VERSION 5.8 ;
BUSBITCHARS "[]" ;
DIVIDERCHAR "/" ;
UNITS
    DATABASE MICRONS 1000 ;
END UNITS

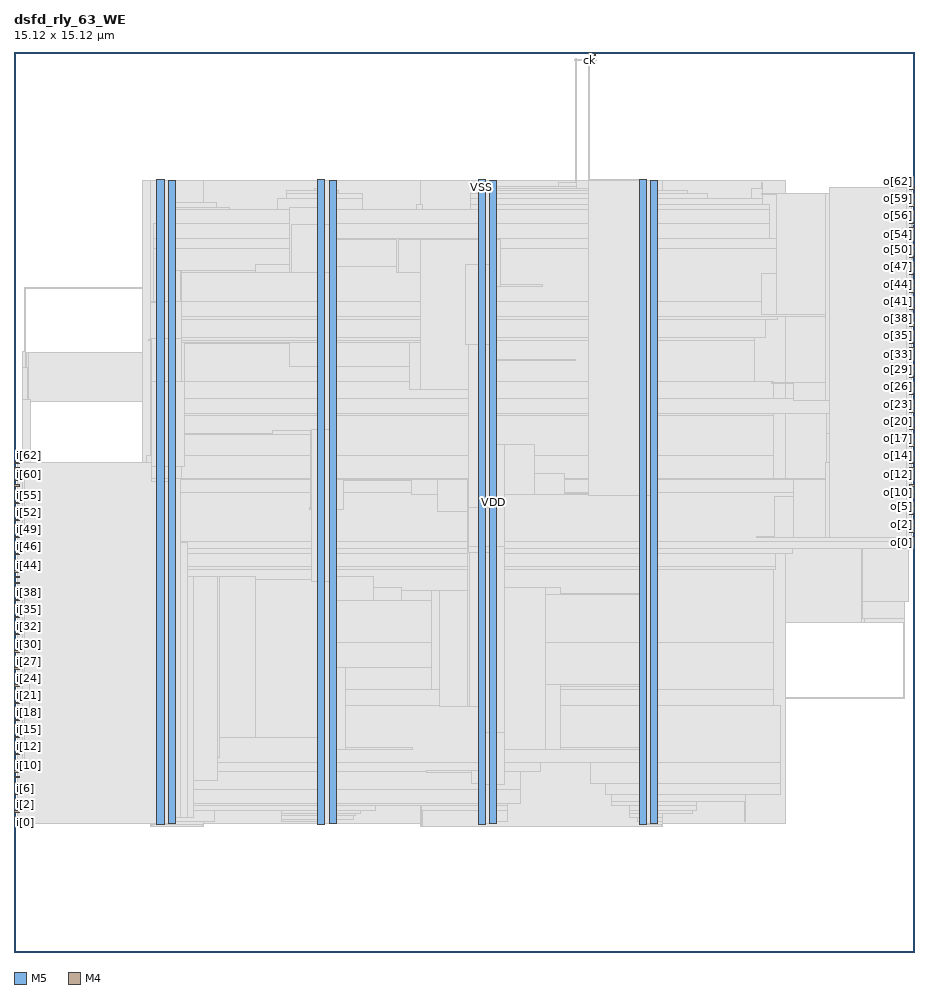
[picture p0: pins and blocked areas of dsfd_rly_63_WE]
MACRO dsfd_rly_63_WE
  FOREIGN dsfd_rly_63_WE 0 0 ;
  CLASS BLOCK ;
  SIZE 15.12 BY 15.12 ;
  PIN ck
    DIRECTION INPUT ;
    USE SIGNAL ;
    PORT
      LAYER M5 ;
        RECT  9.648 15.036 9.672 15.12 ;
    END
  END ck
  PIN i[0]
    DIRECTION INPUT ;
    USE SIGNAL ;
    PORT
      LAYER M4 ;
        RECT  0 2.16 0.084 2.184 ;
    END
  END i[0]
  PIN i[10]
    DIRECTION INPUT ;
    USE SIGNAL ;
    PORT
      LAYER M4 ;
        RECT  0 3.12 0.084 3.144 ;
    END
  END i[10]
  PIN i[11]
    DIRECTION INPUT ;
    USE SIGNAL ;
    PORT
      LAYER M4 ;
        RECT  0 3.216 0.084 3.24 ;
    END
  END i[11]
  PIN i[12]
    DIRECTION INPUT ;
    USE SIGNAL ;
    PORT
      LAYER M4 ;
        RECT  0 3.312 0.084 3.336 ;
    END
  END i[12]
  PIN i[13]
    DIRECTION INPUT ;
    USE SIGNAL ;
    PORT
      LAYER M4 ;
        RECT  0 3.408 0.084 3.432 ;
    END
  END i[13]
  PIN i[14]
    DIRECTION INPUT ;
    USE SIGNAL ;
    PORT
      LAYER M4 ;
        RECT  0 3.504 0.084 3.528 ;
    END
  END i[14]
  PIN i[15]
    DIRECTION INPUT ;
    USE SIGNAL ;
    PORT
      LAYER M4 ;
        RECT  0 3.6 0.084 3.624 ;
    END
  END i[15]
  PIN i[16]
    DIRECTION INPUT ;
    USE SIGNAL ;
    PORT
      LAYER M4 ;
        RECT  0 3.696 0.084 3.72 ;
    END
  END i[16]
  PIN i[17]
    DIRECTION INPUT ;
    USE SIGNAL ;
    PORT
      LAYER M4 ;
        RECT  0 3.792 0.084 3.816 ;
    END
  END i[17]
  PIN i[18]
    DIRECTION INPUT ;
    USE SIGNAL ;
    PORT
      LAYER M4 ;
        RECT  0 3.888 0.084 3.912 ;
    END
  END i[18]
  PIN i[19]
    DIRECTION INPUT ;
    USE SIGNAL ;
    PORT
      LAYER M4 ;
        RECT  0 3.984 0.084 4.008 ;
    END
  END i[19]
  PIN i[1]
    DIRECTION INPUT ;
    USE SIGNAL ;
    PORT
      LAYER M4 ;
        RECT  0 2.256 0.084 2.28 ;
    END
  END i[1]
  PIN i[20]
    DIRECTION INPUT ;
    USE SIGNAL ;
    PORT
      LAYER M4 ;
        RECT  0 4.08 0.084 4.104 ;
    END
  END i[20]
  PIN i[21]
    DIRECTION INPUT ;
    USE SIGNAL ;
    PORT
      LAYER M4 ;
        RECT  0 4.176 0.084 4.2 ;
    END
  END i[21]
  PIN i[22]
    DIRECTION INPUT ;
    USE SIGNAL ;
    PORT
      LAYER M4 ;
        RECT  0 4.272 0.084 4.296 ;
    END
  END i[22]
  PIN i[23]
    DIRECTION INPUT ;
    USE SIGNAL ;
    PORT
      LAYER M4 ;
        RECT  0 4.368 0.084 4.392 ;
    END
  END i[23]
  PIN i[24]
    DIRECTION INPUT ;
    USE SIGNAL ;
    PORT
      LAYER M4 ;
        RECT  0 4.464 0.084 4.488 ;
    END
  END i[24]
  PIN i[25]
    DIRECTION INPUT ;
    USE SIGNAL ;
    PORT
      LAYER M4 ;
        RECT  0 4.56 0.084 4.584 ;
    END
  END i[25]
  PIN i[26]
    DIRECTION INPUT ;
    USE SIGNAL ;
    PORT
      LAYER M4 ;
        RECT  0 4.656 0.084 4.68 ;
    END
  END i[26]
  PIN i[27]
    DIRECTION INPUT ;
    USE SIGNAL ;
    PORT
      LAYER M4 ;
        RECT  0 4.752 0.084 4.776 ;
    END
  END i[27]
  PIN i[28]
    DIRECTION INPUT ;
    USE SIGNAL ;
    PORT
      LAYER M4 ;
        RECT  0 4.848 0.084 4.872 ;
    END
  END i[28]
  PIN i[29]
    DIRECTION INPUT ;
    USE SIGNAL ;
    PORT
      LAYER M4 ;
        RECT  0 4.944 0.084 4.968 ;
    END
  END i[29]
  PIN i[2]
    DIRECTION INPUT ;
    USE SIGNAL ;
    PORT
      LAYER M4 ;
        RECT  0 2.352 0.084 2.376 ;
    END
  END i[2]
  PIN i[30]
    DIRECTION INPUT ;
    USE SIGNAL ;
    PORT
      LAYER M4 ;
        RECT  0 5.04 0.084 5.064 ;
    END
  END i[30]
  PIN i[31]
    DIRECTION INPUT ;
    USE SIGNAL ;
    PORT
      LAYER M4 ;
        RECT  0 5.136 0.084 5.16 ;
    END
  END i[31]
  PIN i[32]
    DIRECTION INPUT ;
    USE SIGNAL ;
    PORT
      LAYER M4 ;
        RECT  0 5.328 0.084 5.352 ;
    END
  END i[32]
  PIN i[33]
    DIRECTION INPUT ;
    USE SIGNAL ;
    PORT
      LAYER M4 ;
        RECT  0 5.424 0.084 5.448 ;
    END
  END i[33]
  PIN i[34]
    DIRECTION INPUT ;
    USE SIGNAL ;
    PORT
      LAYER M4 ;
        RECT  0 5.52 0.084 5.544 ;
    END
  END i[34]
  PIN i[35]
    DIRECTION INPUT ;
    USE SIGNAL ;
    PORT
      LAYER M4 ;
        RECT  0 5.616 0.084 5.64 ;
    END
  END i[35]
  PIN i[36]
    DIRECTION INPUT ;
    USE SIGNAL ;
    PORT
      LAYER M4 ;
        RECT  0 5.712 0.084 5.736 ;
    END
  END i[36]
  PIN i[37]
    DIRECTION INPUT ;
    USE SIGNAL ;
    PORT
      LAYER M4 ;
        RECT  0 5.808 0.084 5.832 ;
    END
  END i[37]
  PIN i[38]
    DIRECTION INPUT ;
    USE SIGNAL ;
    PORT
      LAYER M4 ;
        RECT  0 5.904 0.084 5.928 ;
    END
  END i[38]
  PIN i[39]
    DIRECTION INPUT ;
    USE SIGNAL ;
    PORT
      LAYER M4 ;
        RECT  0 6 0.084 6.024 ;
    END
  END i[39]
  PIN i[3]
    DIRECTION INPUT ;
    USE SIGNAL ;
    PORT
      LAYER M4 ;
        RECT  0 2.448 0.084 2.472 ;
    END
  END i[3]
  PIN i[40]
    DIRECTION INPUT ;
    USE SIGNAL ;
    PORT
      LAYER M4 ;
        RECT  0 6.096 0.084 6.12 ;
    END
  END i[40]
  PIN i[41]
    DIRECTION INPUT ;
    USE SIGNAL ;
    PORT
      LAYER M4 ;
        RECT  0 6.192 0.084 6.216 ;
    END
  END i[41]
  PIN i[42]
    DIRECTION INPUT ;
    USE SIGNAL ;
    PORT
      LAYER M4 ;
        RECT  0 6.288 0.084 6.312 ;
    END
  END i[42]
  PIN i[43]
    DIRECTION INPUT ;
    USE SIGNAL ;
    PORT
      LAYER M4 ;
        RECT  0 6.384 0.084 6.408 ;
    END
  END i[43]
  PIN i[44]
    DIRECTION INPUT ;
    USE SIGNAL ;
    PORT
      LAYER M4 ;
        RECT  0 6.48 0.084 6.504 ;
    END
  END i[44]
  PIN i[45]
    DIRECTION INPUT ;
    USE SIGNAL ;
    PORT
      LAYER M4 ;
        RECT  0 6.576 0.084 6.6 ;
    END
  END i[45]
  PIN i[46]
    DIRECTION INPUT ;
    USE SIGNAL ;
    PORT
      LAYER M4 ;
        RECT  0 6.672 0.084 6.696 ;
    END
  END i[46]
  PIN i[47]
    DIRECTION INPUT ;
    USE SIGNAL ;
    PORT
      LAYER M4 ;
        RECT  0 6.768 0.084 6.792 ;
    END
  END i[47]
  PIN i[48]
    DIRECTION INPUT ;
    USE SIGNAL ;
    PORT
      LAYER M4 ;
        RECT  0 6.864 0.084 6.888 ;
    END
  END i[48]
  PIN i[49]
    DIRECTION INPUT ;
    USE SIGNAL ;
    PORT
      LAYER M4 ;
        RECT  0 6.96 0.084 6.984 ;
    END
  END i[49]
  PIN i[4]
    DIRECTION INPUT ;
    USE SIGNAL ;
    PORT
      LAYER M4 ;
        RECT  0 2.544 0.084 2.568 ;
    END
  END i[4]
  PIN i[50]
    DIRECTION INPUT ;
    USE SIGNAL ;
    PORT
      LAYER M4 ;
        RECT  0 7.056 0.084 7.08 ;
    END
  END i[50]
  PIN i[51]
    DIRECTION INPUT ;
    USE SIGNAL ;
    PORT
      LAYER M4 ;
        RECT  0 7.152 0.084 7.176 ;
    END
  END i[51]
  PIN i[52]
    DIRECTION INPUT ;
    USE SIGNAL ;
    PORT
      LAYER M4 ;
        RECT  0 7.248 0.084 7.272 ;
    END
  END i[52]
  PIN i[53]
    DIRECTION INPUT ;
    USE SIGNAL ;
    PORT
      LAYER M4 ;
        RECT  0 7.344 0.084 7.368 ;
    END
  END i[53]
  PIN i[54]
    DIRECTION INPUT ;
    USE SIGNAL ;
    PORT
      LAYER M4 ;
        RECT  0 7.44 0.084 7.464 ;
    END
  END i[54]
  PIN i[55]
    DIRECTION INPUT ;
    USE SIGNAL ;
    PORT
      LAYER M4 ;
        RECT  0 7.536 0.084 7.56 ;
    END
  END i[55]
  PIN i[56]
    DIRECTION INPUT ;
    USE SIGNAL ;
    PORT
      LAYER M4 ;
        RECT  0 7.632 0.084 7.656 ;
    END
  END i[56]
  PIN i[57]
    DIRECTION INPUT ;
    USE SIGNAL ;
    PORT
      LAYER M4 ;
        RECT  0 7.728 0.084 7.752 ;
    END
  END i[57]
  PIN i[58]
    DIRECTION INPUT ;
    USE SIGNAL ;
    PORT
      LAYER M4 ;
        RECT  0 7.824 0.084 7.848 ;
    END
  END i[58]
  PIN i[59]
    DIRECTION INPUT ;
    USE SIGNAL ;
    PORT
      LAYER M4 ;
        RECT  0 7.92 0.084 7.944 ;
    END
  END i[59]
  PIN i[5]
    DIRECTION INPUT ;
    USE SIGNAL ;
    PORT
      LAYER M4 ;
        RECT  0 2.64 0.084 2.664 ;
    END
  END i[5]
  PIN i[60]
    DIRECTION INPUT ;
    USE SIGNAL ;
    PORT
      LAYER M4 ;
        RECT  0 8.016 0.084 8.04 ;
    END
  END i[60]
  PIN i[61]
    DIRECTION INPUT ;
    USE SIGNAL ;
    PORT
      LAYER M4 ;
        RECT  0 8.112 0.084 8.136 ;
    END
  END i[61]
  PIN i[62]
    DIRECTION INPUT ;
    USE SIGNAL ;
    PORT
      LAYER M4 ;
        RECT  0 8.208 0.084 8.232 ;
    END
  END i[62]
  PIN i[6]
    DIRECTION INPUT ;
    USE SIGNAL ;
    PORT
      LAYER M4 ;
        RECT  0 2.736 0.084 2.76 ;
    END
  END i[6]
  PIN i[7]
    DIRECTION INPUT ;
    USE SIGNAL ;
    PORT
      LAYER M4 ;
        RECT  0 2.832 0.084 2.856 ;
    END
  END i[7]
  PIN i[8]
    DIRECTION INPUT ;
    USE SIGNAL ;
    PORT
      LAYER M4 ;
        RECT  0 2.928 0.084 2.952 ;
    END
  END i[8]
  PIN i[9]
    DIRECTION INPUT ;
    USE SIGNAL ;
    PORT
      LAYER M4 ;
        RECT  0 3.024 0.084 3.048 ;
    END
  END i[9]
  PIN o[0]
    DIRECTION OUTPUT ;
    USE SIGNAL ;
    PORT
      LAYER M4 ;
        RECT  15.036 6.864 15.12 6.888 ;
    END
  END o[0]
  PIN o[10]
    DIRECTION OUTPUT ;
    USE SIGNAL ;
    PORT
      LAYER M4 ;
        RECT  15.036 7.824 15.12 7.848 ;
    END
  END o[10]
  PIN o[11]
    DIRECTION OUTPUT ;
    USE SIGNAL ;
    PORT
      LAYER M4 ;
        RECT  15.036 7.92 15.12 7.944 ;
    END
  END o[11]
  PIN o[12]
    DIRECTION OUTPUT ;
    USE SIGNAL ;
    PORT
      LAYER M4 ;
        RECT  15.036 8.016 15.12 8.04 ;
    END
  END o[12]
  PIN o[13]
    DIRECTION OUTPUT ;
    USE SIGNAL ;
    PORT
      LAYER M4 ;
        RECT  15.036 8.112 15.12 8.136 ;
    END
  END o[13]
  PIN o[14]
    DIRECTION OUTPUT ;
    USE SIGNAL ;
    PORT
      LAYER M4 ;
        RECT  15.036 8.208 15.12 8.232 ;
    END
  END o[14]
  PIN o[15]
    DIRECTION OUTPUT ;
    USE SIGNAL ;
    PORT
      LAYER M4 ;
        RECT  15.036 8.304 15.12 8.328 ;
    END
  END o[15]
  PIN o[16]
    DIRECTION OUTPUT ;
    USE SIGNAL ;
    PORT
      LAYER M4 ;
        RECT  15.036 8.4 15.12 8.424 ;
    END
  END o[16]
  PIN o[17]
    DIRECTION OUTPUT ;
    USE SIGNAL ;
    PORT
      LAYER M4 ;
        RECT  15.036 8.496 15.12 8.52 ;
    END
  END o[17]
  PIN o[18]
    DIRECTION OUTPUT ;
    USE SIGNAL ;
    PORT
      LAYER M4 ;
        RECT  15.036 8.592 15.12 8.616 ;
    END
  END o[18]
  PIN o[19]
    DIRECTION OUTPUT ;
    USE SIGNAL ;
    PORT
      LAYER M4 ;
        RECT  15.036 8.688 15.12 8.712 ;
    END
  END o[19]
  PIN o[1]
    DIRECTION OUTPUT ;
    USE SIGNAL ;
    PORT
      LAYER M4 ;
        RECT  15.036 6.96 15.12 6.984 ;
    END
  END o[1]
  PIN o[20]
    DIRECTION OUTPUT ;
    USE SIGNAL ;
    PORT
      LAYER M4 ;
        RECT  15.036 8.784 15.12 8.808 ;
    END
  END o[20]
  PIN o[21]
    DIRECTION OUTPUT ;
    USE SIGNAL ;
    PORT
      LAYER M4 ;
        RECT  15.036 8.88 15.12 8.904 ;
    END
  END o[21]
  PIN o[22]
    DIRECTION OUTPUT ;
    USE SIGNAL ;
    PORT
      LAYER M4 ;
        RECT  15.036 8.976 15.12 9 ;
    END
  END o[22]
  PIN o[23]
    DIRECTION OUTPUT ;
    USE SIGNAL ;
    PORT
      LAYER M4 ;
        RECT  15.036 9.072 15.12 9.096 ;
    END
  END o[23]
  PIN o[24]
    DIRECTION OUTPUT ;
    USE SIGNAL ;
    PORT
      LAYER M4 ;
        RECT  15.036 9.168 15.12 9.192 ;
    END
  END o[24]
  PIN o[25]
    DIRECTION OUTPUT ;
    USE SIGNAL ;
    PORT
      LAYER M4 ;
        RECT  15.036 9.264 15.12 9.288 ;
    END
  END o[25]
  PIN o[26]
    DIRECTION OUTPUT ;
    USE SIGNAL ;
    PORT
      LAYER M4 ;
        RECT  15.036 9.36 15.12 9.384 ;
    END
  END o[26]
  PIN o[27]
    DIRECTION OUTPUT ;
    USE SIGNAL ;
    PORT
      LAYER M4 ;
        RECT  15.036 9.456 15.12 9.48 ;
    END
  END o[27]
  PIN o[28]
    DIRECTION OUTPUT ;
    USE SIGNAL ;
    PORT
      LAYER M4 ;
        RECT  15.036 9.552 15.12 9.576 ;
    END
  END o[28]
  PIN o[29]
    DIRECTION OUTPUT ;
    USE SIGNAL ;
    PORT
      LAYER M4 ;
        RECT  15.036 9.648 15.12 9.672 ;
    END
  END o[29]
  PIN o[2]
    DIRECTION OUTPUT ;
    USE SIGNAL ;
    PORT
      LAYER M4 ;
        RECT  15.036 7.056 15.12 7.08 ;
    END
  END o[2]
  PIN o[30]
    DIRECTION OUTPUT ;
    USE SIGNAL ;
    PORT
      LAYER M4 ;
        RECT  15.036 9.744 15.12 9.768 ;
    END
  END o[30]
  PIN o[31]
    DIRECTION OUTPUT ;
    USE SIGNAL ;
    PORT
      LAYER M4 ;
        RECT  15.036 9.84 15.12 9.864 ;
    END
  END o[31]
  PIN o[32]
    DIRECTION OUTPUT ;
    USE SIGNAL ;
    PORT
      LAYER M4 ;
        RECT  15.036 9.936 15.12 9.96 ;
    END
  END o[32]
  PIN o[33]
    DIRECTION OUTPUT ;
    USE SIGNAL ;
    PORT
      LAYER M4 ;
        RECT  15.036 10.032 15.12 10.056 ;
    END
  END o[33]
  PIN o[34]
    DIRECTION OUTPUT ;
    USE SIGNAL ;
    PORT
      LAYER M4 ;
        RECT  15.036 10.128 15.12 10.152 ;
    END
  END o[34]
  PIN o[35]
    DIRECTION OUTPUT ;
    USE SIGNAL ;
    PORT
      LAYER M4 ;
        RECT  15.036 10.224 15.12 10.248 ;
    END
  END o[35]
  PIN o[36]
    DIRECTION OUTPUT ;
    USE SIGNAL ;
    PORT
      LAYER M4 ;
        RECT  15.036 10.32 15.12 10.344 ;
    END
  END o[36]
  PIN o[37]
    DIRECTION OUTPUT ;
    USE SIGNAL ;
    PORT
      LAYER M4 ;
        RECT  15.036 10.416 15.12 10.44 ;
    END
  END o[37]
  PIN o[38]
    DIRECTION OUTPUT ;
    USE SIGNAL ;
    PORT
      LAYER M4 ;
        RECT  15.036 10.512 15.12 10.536 ;
    END
  END o[38]
  PIN o[39]
    DIRECTION OUTPUT ;
    USE SIGNAL ;
    PORT
      LAYER M4 ;
        RECT  15.036 10.608 15.12 10.632 ;
    END
  END o[39]
  PIN o[3]
    DIRECTION OUTPUT ;
    USE SIGNAL ;
    PORT
      LAYER M4 ;
        RECT  15.036 7.152 15.12 7.176 ;
    END
  END o[3]
  PIN o[40]
    DIRECTION OUTPUT ;
    USE SIGNAL ;
    PORT
      LAYER M4 ;
        RECT  15.036 10.704 15.12 10.728 ;
    END
  END o[40]
  PIN o[41]
    DIRECTION OUTPUT ;
    USE SIGNAL ;
    PORT
      LAYER M4 ;
        RECT  15.036 10.8 15.12 10.824 ;
    END
  END o[41]
  PIN o[42]
    DIRECTION OUTPUT ;
    USE SIGNAL ;
    PORT
      LAYER M4 ;
        RECT  15.036 10.896 15.12 10.92 ;
    END
  END o[42]
  PIN o[43]
    DIRECTION OUTPUT ;
    USE SIGNAL ;
    PORT
      LAYER M4 ;
        RECT  15.036 10.992 15.12 11.016 ;
    END
  END o[43]
  PIN o[44]
    DIRECTION OUTPUT ;
    USE SIGNAL ;
    PORT
      LAYER M4 ;
        RECT  15.036 11.088 15.12 11.112 ;
    END
  END o[44]
  PIN o[45]
    DIRECTION OUTPUT ;
    USE SIGNAL ;
    PORT
      LAYER M4 ;
        RECT  15.036 11.184 15.12 11.208 ;
    END
  END o[45]
  PIN o[46]
    DIRECTION OUTPUT ;
    USE SIGNAL ;
    PORT
      LAYER M4 ;
        RECT  15.036 11.28 15.12 11.304 ;
    END
  END o[46]
  PIN o[47]
    DIRECTION OUTPUT ;
    USE SIGNAL ;
    PORT
      LAYER M4 ;
        RECT  15.036 11.376 15.12 11.4 ;
    END
  END o[47]
  PIN o[48]
    DIRECTION OUTPUT ;
    USE SIGNAL ;
    PORT
      LAYER M4 ;
        RECT  15.036 11.472 15.12 11.496 ;
    END
  END o[48]
  PIN o[49]
    DIRECTION OUTPUT ;
    USE SIGNAL ;
    PORT
      LAYER M4 ;
        RECT  15.036 11.568 15.12 11.592 ;
    END
  END o[49]
  PIN o[4]
    DIRECTION OUTPUT ;
    USE SIGNAL ;
    PORT
      LAYER M4 ;
        RECT  15.036 7.248 15.12 7.272 ;
    END
  END o[4]
  PIN o[50]
    DIRECTION OUTPUT ;
    USE SIGNAL ;
    PORT
      LAYER M4 ;
        RECT  15.036 11.664 15.12 11.688 ;
    END
  END o[50]
  PIN o[51]
    DIRECTION OUTPUT ;
    USE SIGNAL ;
    PORT
      LAYER M4 ;
        RECT  15.036 11.76 15.12 11.784 ;
    END
  END o[51]
  PIN o[52]
    DIRECTION OUTPUT ;
    USE SIGNAL ;
    PORT
      LAYER M4 ;
        RECT  15.036 11.856 15.12 11.88 ;
    END
  END o[52]
  PIN o[53]
    DIRECTION OUTPUT ;
    USE SIGNAL ;
    PORT
      LAYER M4 ;
        RECT  15.036 11.952 15.12 11.976 ;
    END
  END o[53]
  PIN o[54]
    DIRECTION OUTPUT ;
    USE SIGNAL ;
    PORT
      LAYER M4 ;
        RECT  15.036 12.048 15.12 12.072 ;
    END
  END o[54]
  PIN o[55]
    DIRECTION OUTPUT ;
    USE SIGNAL ;
    PORT
      LAYER M4 ;
        RECT  15.036 12.144 15.12 12.168 ;
    END
  END o[55]
  PIN o[56]
    DIRECTION OUTPUT ;
    USE SIGNAL ;
    PORT
      LAYER M4 ;
        RECT  15.036 12.24 15.12 12.264 ;
    END
  END o[56]
  PIN o[57]
    DIRECTION OUTPUT ;
    USE SIGNAL ;
    PORT
      LAYER M4 ;
        RECT  15.036 12.336 15.12 12.36 ;
    END
  END o[57]
  PIN o[58]
    DIRECTION OUTPUT ;
    USE SIGNAL ;
    PORT
      LAYER M4 ;
        RECT  15.036 12.432 15.12 12.456 ;
    END
  END o[58]
  PIN o[59]
    DIRECTION OUTPUT ;
    USE SIGNAL ;
    PORT
      LAYER M4 ;
        RECT  15.036 12.528 15.12 12.552 ;
    END
  END o[59]
  PIN o[5]
    DIRECTION OUTPUT ;
    USE SIGNAL ;
    PORT
      LAYER M4 ;
        RECT  15.036 7.344 15.12 7.368 ;
    END
  END o[5]
  PIN o[60]
    DIRECTION OUTPUT ;
    USE SIGNAL ;
    PORT
      LAYER M4 ;
        RECT  15.036 12.624 15.12 12.648 ;
    END
  END o[60]
  PIN o[61]
    DIRECTION OUTPUT ;
    USE SIGNAL ;
    PORT
      LAYER M4 ;
        RECT  15.036 12.72 15.12 12.744 ;
    END
  END o[61]
  PIN o[62]
    DIRECTION OUTPUT ;
    USE SIGNAL ;
    PORT
      LAYER M4 ;
        RECT  15.036 12.816 15.12 12.84 ;
    END
  END o[62]
  PIN o[6]
    DIRECTION OUTPUT ;
    USE SIGNAL ;
    PORT
      LAYER M4 ;
        RECT  15.036 7.44 15.12 7.464 ;
    END
  END o[6]
  PIN o[7]
    DIRECTION OUTPUT ;
    USE SIGNAL ;
    PORT
      LAYER M4 ;
        RECT  15.036 7.536 15.12 7.56 ;
    END
  END o[7]
  PIN o[8]
    DIRECTION OUTPUT ;
    USE SIGNAL ;
    PORT
      LAYER M4 ;
        RECT  15.036 7.632 15.12 7.656 ;
    END
  END o[8]
  PIN o[9]
    DIRECTION OUTPUT ;
    USE SIGNAL ;
    PORT
      LAYER M4 ;
        RECT  15.036 7.728 15.12 7.752 ;
    END
  END o[9]
  PIN rs
    DIRECTION INPUT ;
    USE SIGNAL ;
    PORT
      LAYER M5 ;
        RECT  9.744 15.036 9.768 15.12 ;
    END
  END rs
  PIN VDD
    DIRECTION INOUT ;
    USE POWER ;
    PORT
      LAYER M5 ;
        RECT  10.692 2.151 10.812 12.969 ;
        RECT  7.992 2.151 8.112 12.969 ;
        RECT  5.292 2.151 5.412 12.969 ;
        RECT  2.592 2.151 2.712 12.969 ;
    END
  END VDD
  PIN VSS
    DIRECTION INOUT ;
    USE GROUND ;
    PORT
      LAYER M5 ;
        RECT  10.5 2.137 10.62 12.983 ;
        RECT  7.8 2.137 7.92 12.983 ;
        RECT  5.1 2.137 5.22 12.983 ;
        RECT  2.4 2.137 2.52 12.983 ;
    END
  END VSS
  OBS
    LAYER RVTN ;
     RECT  2.16 2.16 12.96 2.295 ;
     RECT  2.16 2.565 12.96 2.835 ;
     RECT  2.16 3.105 12.96 3.375 ;
     RECT  2.16 3.645 12.96 3.915 ;
     RECT  2.16 4.185 12.96 4.455 ;
     RECT  2.16 4.725 12.96 4.995 ;
     RECT  2.16 5.265 12.96 5.535 ;
     RECT  2.16 5.805 12.96 6.075 ;
     RECT  2.16 6.345 12.96 6.615 ;
     RECT  2.16 6.885 12.96 7.155 ;
     RECT  2.16 7.425 12.96 7.695 ;
     RECT  2.16 7.965 12.96 8.235 ;
     RECT  2.16 8.505 12.96 8.775 ;
     RECT  2.16 9.045 12.96 9.315 ;
     RECT  2.16 9.585 12.96 9.855 ;
     RECT  2.16 10.125 12.96 10.395 ;
     RECT  2.16 10.665 12.96 10.935 ;
     RECT  2.16 11.205 12.96 11.475 ;
     RECT  2.16 11.745 12.96 12.015 ;
     RECT  2.16 12.285 12.96 12.555 ;
     RECT  2.16 12.825 12.96 12.96 ;
    LAYER RVTP ;
     RECT  2.16 2.295 12.96 2.565 ;
     RECT  2.16 2.835 12.96 3.105 ;
     RECT  2.16 3.375 12.96 3.645 ;
     RECT  2.16 3.915 12.96 4.185 ;
     RECT  2.16 4.455 12.96 4.725 ;
     RECT  2.16 4.995 12.96 5.265 ;
     RECT  2.16 5.535 12.96 5.805 ;
     RECT  2.16 6.075 12.96 6.345 ;
     RECT  2.16 6.615 12.96 6.885 ;
     RECT  2.16 7.155 12.96 7.425 ;
     RECT  2.16 7.695 12.96 7.965 ;
     RECT  2.16 8.235 12.96 8.505 ;
     RECT  2.16 8.775 12.96 9.045 ;
     RECT  2.16 9.315 12.96 9.585 ;
     RECT  2.16 9.855 12.96 10.125 ;
     RECT  2.16 10.395 12.96 10.665 ;
     RECT  2.16 10.935 12.96 11.205 ;
     RECT  2.16 11.475 12.96 11.745 ;
     RECT  2.16 12.015 12.96 12.285 ;
     RECT  2.16 12.555 12.96 12.825 ;
    LAYER M1 ;
     RECT  2.16 2.151 12.96 12.969 ;
    LAYER M2 ;
     RECT  0.103 2.268 0.139 2.286 ;
     RECT  0.139 10.062 0.211 10.08 ;
     RECT  0.211 9.792 0.247 10.08 ;
     RECT  0.139 4.662 0.275 4.68 ;
     RECT  0.103 7.938 0.311 7.956 ;
     RECT  0.139 2.268 2.16 2.556 ;
     RECT  0.103 3.312 2.16 3.708 ;
     RECT  2.047 7.704 2.16 7.722 ;
     RECT  0.247 9.252 2.16 10.08 ;
     RECT  0.175 11.142 2.16 11.16 ;
     RECT  2.16 2.151 2.299 12.969 ;
     RECT  2.299 2.106 3.191 12.969 ;
     RECT  3.191 2.151 6.835 12.969 ;
     RECT  6.835 2.106 10.895 12.969 ;
     RECT  10.895 2.151 12.96 12.969 ;
     RECT  12.96 5.544 14.243 12.744 ;
     RECT  14.243 9.396 14.279 11.394 ;
     RECT  14.243 5.544 14.315 8.604 ;
     RECT  14.315 5.886 14.351 8.532 ;
     RECT  14.351 7.398 14.387 8.532 ;
     RECT  14.387 7.434 14.459 8.532 ;
     RECT  14.351 5.886 14.855 6.264 ;
     RECT  12.96 4.266 14.963 4.284 ;
     RECT  14.855 5.886 14.999 6.174 ;
     RECT  14.459 7.821 14.999 8.532 ;
     RECT  14.279 9.396 14.999 10.584 ;
     RECT  14.999 5.886 15.035 5.904 ;
     RECT  14.999 7.938 15.035 8.532 ;
     RECT  14.999 10.476 15.035 10.584 ;
     RECT  14.279 11.376 15.035 11.394 ;
     RECT  15.035 10.566 15.107 10.584 ;
     RECT  15.007 12.222 15.107 12.24 ;
    LAYER M3 ;
     RECT  2.304 2.101 2.322 2.143 ;
     RECT  3.168 2.101 3.186 2.143 ;
     RECT  10.872 2.101 10.89 2.143 ;
     RECT  2.304 2.143 3.186 2.191 ;
     RECT  5.115 2.143 5.205 2.191 ;
     RECT  7.815 2.143 7.905 2.191 ;
     RECT  10.515 2.143 10.89 2.191 ;
     RECT  4.5 2.191 5.205 2.227 ;
     RECT  10.476 2.191 10.89 2.263 ;
     RECT  4.5 2.227 5.706 2.299 ;
     RECT  4.5 2.299 5.742 2.335 ;
     RECT  10.332 2.263 10.89 2.335 ;
     RECT  2.304 2.191 3.366 2.371 ;
     RECT  4.5 2.335 5.814 2.371 ;
     RECT  6.84 2.101 6.858 2.371 ;
     RECT  7.815 2.191 8.298 2.371 ;
     RECT  10.332 2.335 11.394 2.371 ;
     RECT  2.304 2.371 6.066 2.461 ;
     RECT  6.84 2.371 8.298 2.461 ;
     RECT  10.332 2.371 11.466 2.461 ;
     RECT  2.304 2.461 8.298 2.497 ;
     RECT  0.108 2.263 0.126 2.533 ;
     RECT  10.044 2.461 11.466 2.533 ;
     RECT  12.276 2.191 12.294 2.533 ;
     RECT  10.044 2.533 12.294 2.641 ;
     RECT  2.304 2.497 8.514 2.731 ;
     RECT  9.936 2.641 12.87 2.839 ;
     RECT  2.268 2.731 8.514 3.037 ;
     RECT  2.268 3.037 8.838 3.181 ;
     RECT  9.684 2.839 12.87 3.181 ;
     RECT  0.108 2.533 0.162 3.211 ;
     RECT  0.108 3.211 0.342 3.341 ;
     RECT  0.108 3.341 0.198 3.869 ;
     RECT  0.108 3.869 0.126 4.013 ;
     RECT  2.268 3.181 12.87 4.145 ;
     RECT  2.268 4.145 12.762 4.415 ;
     RECT  0.144 4.648 0.162 4.657 ;
     RECT  0.144 4.657 0.27 4.843 ;
     RECT  0.144 4.843 0.342 4.973 ;
     RECT  0.144 4.973 0.162 5.117 ;
     RECT  2.304 4.415 12.762 5.197 ;
     RECT  14.94 4.261 14.958 5.539 ;
     RECT  14.292 5.539 14.958 5.611 ;
     RECT  14.256 5.611 14.958 5.881 ;
     RECT  0.324 5.899 0.342 6.029 ;
     RECT  2.268 5.197 12.762 6.421 ;
     RECT  2.268 6.421 12.798 6.475 ;
     RECT  2.052 6.475 12.798 6.691 ;
     RECT  2.052 6.691 13.086 6.781 ;
     RECT  14.256 5.881 15.03 6.781 ;
     RECT  2.052 6.781 15.03 6.893 ;
     RECT  0.324 7.051 0.342 7.243 ;
     RECT  0.252 7.243 0.342 7.435 ;
     RECT  0.252 7.435 0.378 7.627 ;
     RECT  2.052 6.893 14.994 7.727 ;
     RECT  0.216 7.627 0.378 7.757 ;
     RECT  0.216 7.757 0.306 7.819 ;
     RECT  0.144 7.819 0.306 7.915 ;
     RECT  2.232 7.727 14.994 7.933 ;
     RECT  2.232 7.933 15.03 7.949 ;
     RECT  0.108 7.915 0.306 7.961 ;
     RECT  2.232 7.949 12.762 8.339 ;
     RECT  13.644 7.949 15.03 8.717 ;
     RECT  2.304 8.339 12.762 9.005 ;
     RECT  2.376 9.005 12.762 9.049 ;
     RECT  13.644 8.717 14.994 9.049 ;
     RECT  0.144 7.961 0.27 9.275 ;
     RECT  2.376 9.049 14.994 9.293 ;
     RECT  2.376 9.293 12.762 9.581 ;
     RECT  13.644 9.293 14.994 9.739 ;
     RECT  0.144 9.275 0.234 9.815 ;
     RECT  0.144 9.815 0.198 10.085 ;
     RECT  2.376 9.581 12.438 10.267 ;
     RECT  2.304 10.267 12.438 10.327 ;
     RECT  13.644 9.739 15.03 10.561 ;
     RECT  2.304 10.327 12.618 10.633 ;
     RECT  13.644 10.561 15.102 10.637 ;
     RECT  2.304 10.633 12.834 10.669 ;
     RECT  13.644 10.637 14.274 10.669 ;
     RECT  2.304 10.669 14.274 10.925 ;
     RECT  13.68 10.925 14.274 11.117 ;
     RECT  0.18 10.085 0.198 11.165 ;
     RECT  15.084 10.637 15.102 11.371 ;
     RECT  2.34 10.925 12.834 11.821 ;
     RECT  13.68 11.117 14.238 11.821 ;
     RECT  2.34 11.821 14.238 11.981 ;
     RECT  2.34 11.981 12.69 12.245 ;
     RECT  15.012 11.371 15.102 12.245 ;
     RECT  15.012 12.245 15.03 12.269 ;
     RECT  2.415 12.245 12.69 12.479 ;
     RECT  2.415 12.479 3.618 12.515 ;
     RECT  6.768 12.479 6.858 12.551 ;
     RECT  7.668 12.479 12.69 12.551 ;
     RECT  13.68 11.981 14.238 12.557 ;
     RECT  2.415 12.515 3.402 12.587 ;
     RECT  4.428 12.479 5.85 12.659 ;
     RECT  7.668 12.551 12.582 12.659 ;
     RECT  2.415 12.587 2.697 12.707 ;
     RECT  4.572 12.659 5.85 12.749 ;
     RECT  7.668 12.659 11.646 12.749 ;
     RECT  13.716 12.557 14.238 12.749 ;
     RECT  4.572 12.749 5.454 12.785 ;
     RECT  7.815 12.749 11.322 12.785 ;
     RECT  5.04 12.785 5.205 12.821 ;
     RECT  7.815 12.785 10.605 12.821 ;
     RECT  12.384 12.659 12.582 12.821 ;
     RECT  13.716 12.749 13.734 12.845 ;
     RECT  7.815 12.821 9.45 12.857 ;
     RECT  9.144 12.857 9.45 12.929 ;
     RECT  12.564 12.821 12.582 12.929 ;
     RECT  2.415 12.707 2.505 12.977 ;
     RECT  5.115 12.821 5.205 12.977 ;
     RECT  7.815 12.857 7.905 12.977 ;
     RECT  10.515 12.821 10.605 12.977 ;
     RECT  9.432 12.929 9.45 15.005 ;
    LAYER M4 ;
     RECT  2.252 10.272 2.293 10.296 ;
     RECT  0.06 2.16 2.408 8.232 ;
     RECT  2.293 10.272 2.408 10.92 ;
     RECT  2.408 2.148 2.512 12.972 ;
     RECT  2.512 2.256 2.704 12.702 ;
     RECT  2.704 2.256 2.801 11.448 ;
     RECT  2.801 7.968 2.819 11.448 ;
     RECT  2.819 8.16 2.867 10.248 ;
     RECT  2.801 2.256 2.909 6.888 ;
     RECT  2.909 2.256 3.017 6.312 ;
     RECT  3.017 2.88 3.413 6.312 ;
     RECT  3.413 3.264 3.449 6.312 ;
     RECT  2.819 11.424 4.057 11.448 ;
     RECT  3.449 3.6 4.061 6.312 ;
     RECT  2.867 8.688 4.345 8.712 ;
     RECT  2.867 10.224 4.633 10.248 ;
     RECT  4.057 11.424 4.633 11.544 ;
     RECT  4.957 7.44 4.981 7.464 ;
     RECT  4.345 8.688 4.981 8.76 ;
     RECT  4.061 3.6 5.108 6.264 ;
     RECT  4.981 7.44 5.108 8.76 ;
     RECT  4.633 9.84 5.108 10.248 ;
     RECT  4.633 11.424 5.108 12.504 ;
     RECT  5.108 2.148 5.212 12.972 ;
     RECT  5.212 2.418 5.404 12.702 ;
     RECT  5.404 7.44 5.537 7.944 ;
     RECT  5.404 3.408 5.573 4.776 ;
     RECT  5.404 5.904 6.041 6.312 ;
     RECT  5.404 11.52 6.421 11.976 ;
     RECT  6.041 5.904 6.509 6.12 ;
     RECT  5.404 9.84 6.649 10.248 ;
     RECT  5.537 7.92 6.685 7.944 ;
     RECT  5.573 3.408 6.689 3.432 ;
     RECT  6.649 9.456 6.829 10.248 ;
     RECT  6.421 11.424 6.829 11.976 ;
     RECT  5.573 4.416 7.009 4.776 ;
     RECT  6.509 5.904 7.009 6.072 ;
     RECT  6.685 7.68 7.117 7.944 ;
     RECT  7.009 4.416 7.153 6.072 ;
     RECT  7.153 4.128 7.621 6.072 ;
     RECT  7.117 7.392 7.621 7.944 ;
     RECT  7.621 4.128 7.657 7.944 ;
     RECT  6.937 3.024 7.693 3.048 ;
     RECT  7.693 2.832 7.808 3.048 ;
     RECT  7.657 4.128 7.808 8.04 ;
     RECT  6.829 9.456 7.808 11.976 ;
     RECT  7.808 2.148 7.912 12.972 ;
     RECT  7.912 2.418 8.104 12.702 ;
     RECT  8.104 11.184 8.165 11.976 ;
     RECT  8.104 2.832 8.243 8.52 ;
     RECT  8.243 7.68 8.741 8.52 ;
     RECT  8.165 11.184 8.885 11.208 ;
     RECT  8.243 3.408 8.921 6.12 ;
     RECT  8.921 3.408 9.173 4.488 ;
     RECT  8.921 6 9.173 6.12 ;
     RECT  8.741 7.68 9.245 8.04 ;
     RECT  8.104 9.936 9.425 9.96 ;
     RECT  9.421 14.976 9.779 15 ;
     RECT  9.245 7.68 10.316 7.704 ;
     RECT  10.316 7.68 10.357 7.8 ;
     RECT  9.173 3.408 10.508 3.432 ;
     RECT  9.173 4.464 10.508 4.488 ;
     RECT  9.173 6 10.508 6.024 ;
     RECT  10.357 7.68 10.508 9.048 ;
     RECT  10.357 10.56 10.508 10.584 ;
     RECT  10.508 2.148 10.612 12.972 ;
     RECT  10.612 2.418 10.804 12.702 ;
     RECT  12.481 6.96 12.769 6.984 ;
     RECT  12.553 10.704 12.805 11.4 ;
     RECT  12.553 12.72 12.805 12.744 ;
     RECT  12.769 6.96 13.093 7.656 ;
     RECT  12.733 9.552 13.093 9.576 ;
     RECT  13.093 6.96 13.633 7.944 ;
     RECT  13.093 9.264 13.633 9.576 ;
     RECT  12.805 10.704 13.633 12.744 ;
     RECT  13.633 6.96 13.705 8.232 ;
     RECT  13.633 9.264 13.705 12.744 ;
     RECT  13.705 6.96 15.001 12.84 ;
     RECT  15.001 6.864 15.084 12.84 ;
    LAYER M5 ;
     RECT  2.4 2.137 2.52 2.151 ;
     RECT  5.1 2.137 5.22 2.151 ;
     RECT  7.8 2.137 7.92 2.151 ;
     RECT  10.5 2.137 10.62 2.151 ;
     RECT  7.8 2.151 8.112 2.821 ;
     RECT  7.8 2.821 8.232 3.683 ;
     RECT  0.144 3.061 0.168 4.069 ;
     RECT  0.144 4.069 0.264 4.691 ;
     RECT  0.144 4.691 0.168 6.035 ;
     RECT  5.1 2.151 5.412 6.229 ;
     RECT  7.8 3.683 8.112 6.709 ;
     RECT  7.632 6.709 8.112 6.805 ;
     RECT  7.632 6.805 8.232 7.475 ;
     RECT  10.5 2.151 10.812 7.669 ;
     RECT  2.4 2.151 2.712 7.909 ;
     RECT  2.304 7.909 2.712 7.957 ;
     RECT  0.144 7.141 0.168 8.003 ;
     RECT  2.304 7.957 2.808 8.149 ;
     RECT  4.992 6.229 5.412 8.771 ;
     RECT  2.304 8.149 2.856 9.587 ;
     RECT  7.632 7.475 8.112 10.213 ;
     RECT  2.304 9.587 2.808 10.307 ;
     RECT  2.4 10.307 2.808 10.931 ;
     RECT  5.1 8.771 5.412 11.413 ;
     RECT  7.584 10.213 8.112 11.555 ;
     RECT  6.432 11.413 6.456 11.987 ;
     RECT  4.656 11.413 5.412 12.227 ;
     RECT  2.4 10.931 2.712 12.969 ;
     RECT  5.1 12.227 5.412 12.969 ;
     RECT  7.8 11.555 8.112 12.969 ;
     RECT  9.648 7.669 10.812 12.969 ;
     RECT  2.4 12.969 2.52 12.983 ;
     RECT  5.1 12.969 5.22 12.983 ;
     RECT  7.8 12.969 7.92 12.983 ;
     RECT  9.648 12.969 10.62 12.983 ;
     RECT  9.648 12.983 9.672 14.965 ;
     RECT  9.648 14.965 9.768 15.056 ;
  END
END dsfd_rly_63_WE
END LIBRARY
